VERSION 5.7 ;
  NOWIREEXTENSIONATPIN ON ;
  DIVIDERCHAR "/" ;
  BUSBITCHARS "[]" ;
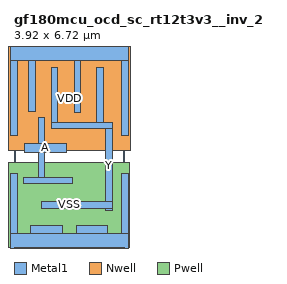
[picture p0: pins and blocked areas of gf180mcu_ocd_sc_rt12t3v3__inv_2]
MACRO gf180mcu_ocd_sc_rt12t3v3__inv_2
  CLASS CORE ;
  FOREIGN gf180mcu_ocd_sc_rt12t3v3__inv_2 ;
  ORIGIN 0.000 0.000 ;
  SIZE 3.920 BY 6.720 ;
  SYMMETRY X Y ;
  SITE unithd ;
  PIN A
    DIRECTION INPUT ;
    USE SIGNAL ;
    ANTENNAGATEAREA 3.346000 ;
    PORT
      LAYER Metal1 ;
        RECT 0.865 3.490 1.095 4.395 ;
        RECT 0.370 3.160 1.870 3.490 ;
        RECT 0.865 2.285 1.095 3.160 ;
        RECT 0.345 2.055 2.070 2.285 ;
    END
  END A
  PIN Y
    DIRECTION OUTPUT ;
    USE SIGNAL ;
    ANTENNADIFFAREA 2.263800 ;
    PORT
      LAYER Metal1 ;
        RECT 1.325 4.240 1.555 6.180 ;
        RECT 2.925 4.240 3.155 6.180 ;
        RECT 1.325 4.010 3.490 4.240 ;
        RECT 3.230 1.425 3.490 4.010 ;
        RECT 0.980 1.195 3.490 1.425 ;
        RECT 3.230 1.120 3.490 1.195 ;
    END
  END Y
  PIN VDD
    DIRECTION INOUT ;
    USE POWER ;
    SHAPE ABUTMENT ;
    PORT
      LAYER Nwell ;
        RECT -0.610 3.245 4.530 7.330 ;
      LAYER Metal1 ;
        RECT -0.115 6.420 4.035 7.020 ;
        RECT -0.115 3.750 0.115 6.420 ;
        RECT 0.525 4.630 0.755 6.420 ;
        RECT 2.125 4.585 2.355 6.420 ;
        RECT 3.805 3.750 4.035 6.420 ;
    END
  END VDD
  PIN VSS
    DIRECTION INOUT ;
    USE GROUND ;
    SHAPE ABUTMENT ;
    PORT
      LAYER Pwell ;
        RECT -0.180 -0.180 4.100 2.815 ;
        RECT 0.000 -0.300 3.920 -0.180 ;
      LAYER Metal1 ;
        RECT -0.115 0.300 0.115 2.410 ;
        RECT 0.600 0.300 1.710 0.585 ;
        RECT 2.220 0.300 3.320 0.585 ;
        RECT 3.805 0.300 4.035 2.410 ;
        RECT -0.115 -0.300 4.035 0.300 ;
    END
  END VSS
END gf180mcu_ocd_sc_rt12t3v3__inv_2
END LIBRARY

